VERSION 5.8 ;
BUSBITCHARS "[]" ;
DIVIDERCHAR "/" ;
UNITS
    DATABASE MICRONS 1000 ;
END UNITS

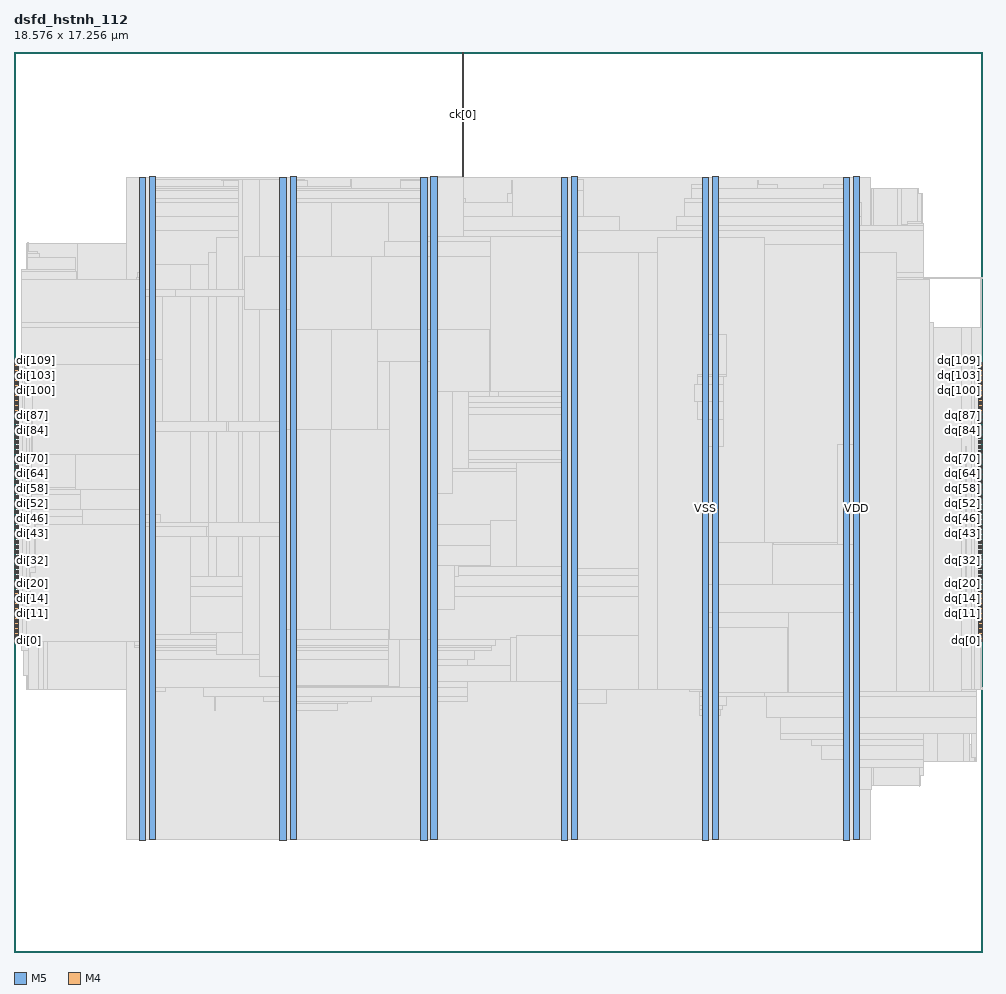
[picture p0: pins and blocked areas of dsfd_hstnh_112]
MACRO dsfd_hstnh_112
  FOREIGN dsfd_hstnh_112 0 0 ;
  CLASS BLOCK ;
  SIZE 18.576 BY 17.256 ;
  PIN ck[0]
    DIRECTION INPUT ;
    USE SIGNAL ;
    PORT
      LAYER M5 ;
        RECT  8.592 17.172 8.616 17.256 ;
    END
    PORT
      LAYER M5 ;
        RECT  8.592 14.873 8.616 17.232 ;
    END
  END ck[0]
  PIN di[0]
    DIRECTION INPUT ;
    USE SIGNAL ;
    PORT
      LAYER M4 ;
        RECT  0 5.952 0.084 5.976 ;
    END
  END di[0]
  PIN di[100]
    DIRECTION INPUT ;
    USE SIGNAL ;
    PORT
      LAYER M4 ;
        RECT  0 10.752 0.084 10.776 ;
    END
  END di[100]
  PIN di[101]
    DIRECTION INPUT ;
    USE SIGNAL ;
    PORT
      LAYER M4 ;
        RECT  0 10.8 0.084 10.824 ;
    END
  END di[101]
  PIN di[102]
    DIRECTION INPUT ;
    USE SIGNAL ;
    PORT
      LAYER M4 ;
        RECT  0 10.848 0.084 10.872 ;
    END
  END di[102]
  PIN di[103]
    DIRECTION INPUT ;
    USE SIGNAL ;
    PORT
      LAYER M4 ;
        RECT  0 10.896 0.084 10.92 ;
    END
  END di[103]
  PIN di[104]
    DIRECTION INPUT ;
    USE SIGNAL ;
    PORT
      LAYER M4 ;
        RECT  0 10.944 0.084 10.968 ;
    END
  END di[104]
  PIN di[105]
    DIRECTION INPUT ;
    USE SIGNAL ;
    PORT
      LAYER M4 ;
        RECT  0 10.992 0.084 11.016 ;
    END
  END di[105]
  PIN di[106]
    DIRECTION INPUT ;
    USE SIGNAL ;
    PORT
      LAYER M4 ;
        RECT  0 11.04 0.084 11.064 ;
    END
  END di[106]
  PIN di[107]
    DIRECTION INPUT ;
    USE SIGNAL ;
    PORT
      LAYER M4 ;
        RECT  0 11.088 0.084 11.112 ;
    END
  END di[107]
  PIN di[108]
    DIRECTION INPUT ;
    USE SIGNAL ;
    PORT
      LAYER M4 ;
        RECT  0 11.136 0.084 11.16 ;
    END
  END di[108]
  PIN di[109]
    DIRECTION INPUT ;
    USE SIGNAL ;
    PORT
      LAYER M4 ;
        RECT  0 11.184 0.084 11.208 ;
    END
  END di[109]
  PIN di[10]
    DIRECTION INPUT ;
    USE SIGNAL ;
    PORT
      LAYER M4 ;
        RECT  0 6.432 0.084 6.456 ;
    END
  END di[10]
  PIN di[110]
    DIRECTION INPUT ;
    USE SIGNAL ;
    PORT
      LAYER M4 ;
        RECT  0 11.232 0.084 11.256 ;
    END
  END di[110]
  PIN di[111]
    DIRECTION INPUT ;
    USE SIGNAL ;
    PORT
      LAYER M4 ;
        RECT  0 11.28 0.084 11.304 ;
    END
  END di[111]
  PIN di[11]
    DIRECTION INPUT ;
    USE SIGNAL ;
    PORT
      LAYER M4 ;
        RECT  0 6.48 0.084 6.504 ;
    END
  END di[11]
  PIN di[12]
    DIRECTION INPUT ;
    USE SIGNAL ;
    PORT
      LAYER M4 ;
        RECT  0 6.528 0.084 6.552 ;
    END
  END di[12]
  PIN di[13]
    DIRECTION INPUT ;
    USE SIGNAL ;
    PORT
      LAYER M4 ;
        RECT  0 6.576 0.084 6.6 ;
    END
  END di[13]
  PIN di[14]
    DIRECTION INPUT ;
    USE SIGNAL ;
    PORT
      LAYER M4 ;
        RECT  0 6.624 0.084 6.648 ;
    END
  END di[14]
  PIN di[15]
    DIRECTION INPUT ;
    USE SIGNAL ;
    PORT
      LAYER M4 ;
        RECT  0 6.672 0.084 6.696 ;
    END
  END di[15]
  PIN di[16]
    DIRECTION INPUT ;
    USE SIGNAL ;
    PORT
      LAYER M4 ;
        RECT  0 6.72 0.084 6.744 ;
    END
  END di[16]
  PIN di[17]
    DIRECTION INPUT ;
    USE SIGNAL ;
    PORT
      LAYER M4 ;
        RECT  0 6.768 0.084 6.792 ;
    END
  END di[17]
  PIN di[18]
    DIRECTION INPUT ;
    USE SIGNAL ;
    PORT
      LAYER M4 ;
        RECT  0 6.816 0.084 6.84 ;
    END
  END di[18]
  PIN di[19]
    DIRECTION INPUT ;
    USE SIGNAL ;
    PORT
      LAYER M4 ;
        RECT  0 6.864 0.084 6.888 ;
    END
  END di[19]
  PIN di[1]
    DIRECTION INPUT ;
    USE SIGNAL ;
    PORT
      LAYER M4 ;
        RECT  0 6 0.084 6.024 ;
    END
  END di[1]
  PIN di[20]
    DIRECTION INPUT ;
    USE SIGNAL ;
    PORT
      LAYER M4 ;
        RECT  0 6.912 0.084 6.936 ;
    END
  END di[20]
  PIN di[21]
    DIRECTION INPUT ;
    USE SIGNAL ;
    PORT
      LAYER M4 ;
        RECT  0 6.96 0.084 6.984 ;
    END
  END di[21]
  PIN di[22]
    DIRECTION INPUT ;
    USE SIGNAL ;
    PORT
      LAYER M4 ;
        RECT  0 7.008 0.084 7.032 ;
    END
  END di[22]
  PIN di[23]
    DIRECTION INPUT ;
    USE SIGNAL ;
    PORT
      LAYER M4 ;
        RECT  0 7.056 0.084 7.08 ;
    END
  END di[23]
  PIN di[24]
    DIRECTION INPUT ;
    USE SIGNAL ;
    PORT
      LAYER M4 ;
        RECT  0 7.104 0.084 7.128 ;
    END
  END di[24]
  PIN di[25]
    DIRECTION INPUT ;
    USE SIGNAL ;
    PORT
      LAYER M4 ;
        RECT  0 7.152 0.084 7.176 ;
    END
  END di[25]
  PIN di[26]
    DIRECTION INPUT ;
    USE SIGNAL ;
    PORT
      LAYER M4 ;
        RECT  0 7.2 0.084 7.224 ;
    END
  END di[26]
  PIN di[27]
    DIRECTION INPUT ;
    USE SIGNAL ;
    PORT
      LAYER M4 ;
        RECT  0 7.248 0.084 7.272 ;
    END
  END di[27]
  PIN di[28]
    DIRECTION INPUT ;
    USE SIGNAL ;
    PORT
      LAYER M4 ;
        RECT  0 7.296 0.084 7.32 ;
    END
  END di[28]
  PIN di[29]
    DIRECTION INPUT ;
    USE SIGNAL ;
    PORT
      LAYER M4 ;
        RECT  0 7.344 0.084 7.368 ;
    END
  END di[29]
  PIN di[2]
    DIRECTION INPUT ;
    USE SIGNAL ;
    PORT
      LAYER M4 ;
        RECT  0 6.048 0.084 6.072 ;
    END
  END di[2]
  PIN di[30]
    DIRECTION INPUT ;
    USE SIGNAL ;
    PORT
      LAYER M4 ;
        RECT  0 7.392 0.084 7.416 ;
    END
  END di[30]
  PIN di[31]
    DIRECTION INPUT ;
    USE SIGNAL ;
    PORT
      LAYER M4 ;
        RECT  0 7.44 0.084 7.464 ;
    END
  END di[31]
  PIN di[32]
    DIRECTION INPUT ;
    USE SIGNAL ;
    PORT
      LAYER M4 ;
        RECT  0 7.488 0.084 7.512 ;
    END
  END di[32]
  PIN di[33]
    DIRECTION INPUT ;
    USE SIGNAL ;
    PORT
      LAYER M4 ;
        RECT  0 7.536 0.084 7.56 ;
    END
  END di[33]
  PIN di[34]
    DIRECTION INPUT ;
    USE SIGNAL ;
    PORT
      LAYER M4 ;
        RECT  0 7.584 0.084 7.608 ;
    END
  END di[34]
  PIN di[35]
    DIRECTION INPUT ;
    USE SIGNAL ;
    PORT
      LAYER M4 ;
        RECT  0 7.632 0.084 7.656 ;
    END
  END di[35]
  PIN di[36]
    DIRECTION INPUT ;
    USE SIGNAL ;
    PORT
      LAYER M4 ;
        RECT  0 7.68 0.084 7.704 ;
    END
  END di[36]
  PIN di[37]
    DIRECTION INPUT ;
    USE SIGNAL ;
    PORT
      LAYER M4 ;
        RECT  0 7.728 0.084 7.752 ;
    END
  END di[37]
  PIN di[38]
    DIRECTION INPUT ;
    USE SIGNAL ;
    PORT
      LAYER M4 ;
        RECT  0 7.776 0.084 7.8 ;
    END
  END di[38]
  PIN di[39]
    DIRECTION INPUT ;
    USE SIGNAL ;
    PORT
      LAYER M4 ;
        RECT  0 7.824 0.084 7.848 ;
    END
  END di[39]
  PIN di[3]
    DIRECTION INPUT ;
    USE SIGNAL ;
    PORT
      LAYER M4 ;
        RECT  0 6.096 0.084 6.12 ;
    END
  END di[3]
  PIN di[40]
    DIRECTION INPUT ;
    USE SIGNAL ;
    PORT
      LAYER M4 ;
        RECT  0 7.872 0.084 7.896 ;
    END
  END di[40]
  PIN di[41]
    DIRECTION INPUT ;
    USE SIGNAL ;
    PORT
      LAYER M4 ;
        RECT  0 7.92 0.084 7.944 ;
    END
  END di[41]
  PIN di[42]
    DIRECTION INPUT ;
    USE SIGNAL ;
    PORT
      LAYER M4 ;
        RECT  0 7.968 0.084 7.992 ;
    END
  END di[42]
  PIN di[43]
    DIRECTION INPUT ;
    USE SIGNAL ;
    PORT
      LAYER M4 ;
        RECT  0 8.016 0.084 8.04 ;
    END
  END di[43]
  PIN di[44]
    DIRECTION INPUT ;
    USE SIGNAL ;
    PORT
      LAYER M4 ;
        RECT  0 8.064 0.084 8.088 ;
    END
  END di[44]
  PIN di[45]
    DIRECTION INPUT ;
    USE SIGNAL ;
    PORT
      LAYER M4 ;
        RECT  0 8.112 0.084 8.136 ;
    END
  END di[45]
  PIN di[46]
    DIRECTION INPUT ;
    USE SIGNAL ;
    PORT
      LAYER M4 ;
        RECT  0 8.16 0.084 8.184 ;
    END
  END di[46]
  PIN di[47]
    DIRECTION INPUT ;
    USE SIGNAL ;
    PORT
      LAYER M4 ;
        RECT  0 8.208 0.084 8.232 ;
    END
  END di[47]
  PIN di[48]
    DIRECTION INPUT ;
    USE SIGNAL ;
    PORT
      LAYER M4 ;
        RECT  0 8.256 0.084 8.28 ;
    END
  END di[48]
  PIN di[49]
    DIRECTION INPUT ;
    USE SIGNAL ;
    PORT
      LAYER M4 ;
        RECT  0 8.304 0.084 8.328 ;
    END
  END di[49]
  PIN di[4]
    DIRECTION INPUT ;
    USE SIGNAL ;
    PORT
      LAYER M4 ;
        RECT  0 6.144 0.084 6.168 ;
    END
  END di[4]
  PIN di[50]
    DIRECTION INPUT ;
    USE SIGNAL ;
    PORT
      LAYER M4 ;
        RECT  0 8.352 0.084 8.376 ;
    END
  END di[50]
  PIN di[51]
    DIRECTION INPUT ;
    USE SIGNAL ;
    PORT
      LAYER M4 ;
        RECT  0 8.4 0.084 8.424 ;
    END
  END di[51]
  PIN di[52]
    DIRECTION INPUT ;
    USE SIGNAL ;
    PORT
      LAYER M4 ;
        RECT  0 8.448 0.084 8.472 ;
    END
  END di[52]
  PIN di[53]
    DIRECTION INPUT ;
    USE SIGNAL ;
    PORT
      LAYER M4 ;
        RECT  0 8.496 0.084 8.52 ;
    END
  END di[53]
  PIN di[54]
    DIRECTION INPUT ;
    USE SIGNAL ;
    PORT
      LAYER M4 ;
        RECT  0 8.544 0.084 8.568 ;
    END
  END di[54]
  PIN di[55]
    DIRECTION INPUT ;
    USE SIGNAL ;
    PORT
      LAYER M4 ;
        RECT  0 8.592 0.084 8.616 ;
    END
  END di[55]
  PIN di[56]
    DIRECTION INPUT ;
    USE SIGNAL ;
    PORT
      LAYER M4 ;
        RECT  0 8.64 0.084 8.664 ;
    END
  END di[56]
  PIN di[57]
    DIRECTION INPUT ;
    USE SIGNAL ;
    PORT
      LAYER M4 ;
        RECT  0 8.688 0.084 8.712 ;
    END
  END di[57]
  PIN di[58]
    DIRECTION INPUT ;
    USE SIGNAL ;
    PORT
      LAYER M4 ;
        RECT  0 8.736 0.084 8.76 ;
    END
  END di[58]
  PIN di[59]
    DIRECTION INPUT ;
    USE SIGNAL ;
    PORT
      LAYER M4 ;
        RECT  0 8.784 0.084 8.808 ;
    END
  END di[59]
  PIN di[5]
    DIRECTION INPUT ;
    USE SIGNAL ;
    PORT
      LAYER M4 ;
        RECT  0 6.192 0.084 6.216 ;
    END
  END di[5]
  PIN di[60]
    DIRECTION INPUT ;
    USE SIGNAL ;
    PORT
      LAYER M4 ;
        RECT  0 8.832 0.084 8.856 ;
    END
  END di[60]
  PIN di[61]
    DIRECTION INPUT ;
    USE SIGNAL ;
    PORT
      LAYER M4 ;
        RECT  0 8.88 0.084 8.904 ;
    END
  END di[61]
  PIN di[62]
    DIRECTION INPUT ;
    USE SIGNAL ;
    PORT
      LAYER M4 ;
        RECT  0 8.928 0.084 8.952 ;
    END
  END di[62]
  PIN di[63]
    DIRECTION INPUT ;
    USE SIGNAL ;
    PORT
      LAYER M4 ;
        RECT  0 8.976 0.084 9 ;
    END
  END di[63]
  PIN di[64]
    DIRECTION INPUT ;
    USE SIGNAL ;
    PORT
      LAYER M4 ;
        RECT  0 9.024 0.084 9.048 ;
    END
  END di[64]
  PIN di[65]
    DIRECTION INPUT ;
    USE SIGNAL ;
    PORT
      LAYER M4 ;
        RECT  0 9.072 0.084 9.096 ;
    END
  END di[65]
  PIN di[66]
    DIRECTION INPUT ;
    USE SIGNAL ;
    PORT
      LAYER M4 ;
        RECT  0 9.12 0.084 9.144 ;
    END
  END di[66]
  PIN di[67]
    DIRECTION INPUT ;
    USE SIGNAL ;
    PORT
      LAYER M4 ;
        RECT  0 9.168 0.084 9.192 ;
    END
  END di[67]
  PIN di[68]
    DIRECTION INPUT ;
    USE SIGNAL ;
    PORT
      LAYER M4 ;
        RECT  0 9.216 0.084 9.24 ;
    END
  END di[68]
  PIN di[69]
    DIRECTION INPUT ;
    USE SIGNAL ;
    PORT
      LAYER M4 ;
        RECT  0 9.264 0.084 9.288 ;
    END
  END di[69]
  PIN di[6]
    DIRECTION INPUT ;
    USE SIGNAL ;
    PORT
      LAYER M4 ;
        RECT  0 6.24 0.084 6.264 ;
    END
  END di[6]
  PIN di[70]
    DIRECTION INPUT ;
    USE SIGNAL ;
    PORT
      LAYER M4 ;
        RECT  0 9.312 0.084 9.336 ;
    END
  END di[70]
  PIN di[71]
    DIRECTION INPUT ;
    USE SIGNAL ;
    PORT
      LAYER M4 ;
        RECT  0 9.36 0.084 9.384 ;
    END
  END di[71]
  PIN di[72]
    DIRECTION INPUT ;
    USE SIGNAL ;
    PORT
      LAYER M4 ;
        RECT  0 9.408 0.084 9.432 ;
    END
  END di[72]
  PIN di[73]
    DIRECTION INPUT ;
    USE SIGNAL ;
    PORT
      LAYER M4 ;
        RECT  0 9.456 0.084 9.48 ;
    END
  END di[73]
  PIN di[74]
    DIRECTION INPUT ;
    USE SIGNAL ;
    PORT
      LAYER M4 ;
        RECT  0 9.504 0.084 9.528 ;
    END
  END di[74]
  PIN di[75]
    DIRECTION INPUT ;
    USE SIGNAL ;
    PORT
      LAYER M4 ;
        RECT  0 9.552 0.084 9.576 ;
    END
  END di[75]
  PIN di[76]
    DIRECTION INPUT ;
    USE SIGNAL ;
    PORT
      LAYER M4 ;
        RECT  0 9.6 0.084 9.624 ;
    END
  END di[76]
  PIN di[77]
    DIRECTION INPUT ;
    USE SIGNAL ;
    PORT
      LAYER M4 ;
        RECT  0 9.648 0.084 9.672 ;
    END
  END di[77]
  PIN di[78]
    DIRECTION INPUT ;
    USE SIGNAL ;
    PORT
      LAYER M4 ;
        RECT  0 9.696 0.084 9.72 ;
    END
  END di[78]
  PIN di[79]
    DIRECTION INPUT ;
    USE SIGNAL ;
    PORT
      LAYER M4 ;
        RECT  0 9.744 0.084 9.768 ;
    END
  END di[79]
  PIN di[7]
    DIRECTION INPUT ;
    USE SIGNAL ;
    PORT
      LAYER M4 ;
        RECT  0 6.288 0.084 6.312 ;
    END
  END di[7]
  PIN di[80]
    DIRECTION INPUT ;
    USE SIGNAL ;
    PORT
      LAYER M4 ;
        RECT  0 9.792 0.084 9.816 ;
    END
  END di[80]
  PIN di[81]
    DIRECTION INPUT ;
    USE SIGNAL ;
    PORT
      LAYER M4 ;
        RECT  0 9.84 0.084 9.864 ;
    END
  END di[81]
  PIN di[82]
    DIRECTION INPUT ;
    USE SIGNAL ;
    PORT
      LAYER M4 ;
        RECT  0 9.888 0.084 9.912 ;
    END
  END di[82]
  PIN di[83]
    DIRECTION INPUT ;
    USE SIGNAL ;
    PORT
      LAYER M4 ;
        RECT  0 9.936 0.084 9.96 ;
    END
  END di[83]
  PIN di[84]
    DIRECTION INPUT ;
    USE SIGNAL ;
    PORT
      LAYER M4 ;
        RECT  0 9.984 0.084 10.008 ;
    END
  END di[84]
  PIN di[85]
    DIRECTION INPUT ;
    USE SIGNAL ;
    PORT
      LAYER M4 ;
        RECT  0 10.032 0.084 10.056 ;
    END
  END di[85]
  PIN di[86]
    DIRECTION INPUT ;
    USE SIGNAL ;
    PORT
      LAYER M4 ;
        RECT  0 10.08 0.084 10.104 ;
    END
  END di[86]
  PIN di[87]
    DIRECTION INPUT ;
    USE SIGNAL ;
    PORT
      LAYER M4 ;
        RECT  0 10.128 0.084 10.152 ;
    END
  END di[87]
  PIN di[88]
    DIRECTION INPUT ;
    USE SIGNAL ;
    PORT
      LAYER M4 ;
        RECT  0 10.176 0.084 10.2 ;
    END
  END di[88]
  PIN di[89]
    DIRECTION INPUT ;
    USE SIGNAL ;
    PORT
      LAYER M4 ;
        RECT  0 10.224 0.084 10.248 ;
    END
  END di[89]
  PIN di[8]
    DIRECTION INPUT ;
    USE SIGNAL ;
    PORT
      LAYER M4 ;
        RECT  0 6.336 0.084 6.36 ;
    END
  END di[8]
  PIN di[90]
    DIRECTION INPUT ;
    USE SIGNAL ;
    PORT
      LAYER M4 ;
        RECT  0 10.272 0.084 10.296 ;
    END
  END di[90]
  PIN di[91]
    DIRECTION INPUT ;
    USE SIGNAL ;
    PORT
      LAYER M4 ;
        RECT  0 10.32 0.084 10.344 ;
    END
  END di[91]
  PIN di[92]
    DIRECTION INPUT ;
    USE SIGNAL ;
    PORT
      LAYER M4 ;
        RECT  0 10.368 0.084 10.392 ;
    END
  END di[92]
  PIN di[93]
    DIRECTION INPUT ;
    USE SIGNAL ;
    PORT
      LAYER M4 ;
        RECT  0 10.416 0.084 10.44 ;
    END
  END di[93]
  PIN di[94]
    DIRECTION INPUT ;
    USE SIGNAL ;
    PORT
      LAYER M4 ;
        RECT  0 10.464 0.084 10.488 ;
    END
  END di[94]
  PIN di[95]
    DIRECTION INPUT ;
    USE SIGNAL ;
    PORT
      LAYER M4 ;
        RECT  0 10.512 0.084 10.536 ;
    END
  END di[95]
  PIN di[96]
    DIRECTION INPUT ;
    USE SIGNAL ;
    PORT
      LAYER M4 ;
        RECT  0 10.56 0.084 10.584 ;
    END
  END di[96]
  PIN di[97]
    DIRECTION INPUT ;
    USE SIGNAL ;
    PORT
      LAYER M4 ;
        RECT  0 10.608 0.084 10.632 ;
    END
  END di[97]
  PIN di[98]
    DIRECTION INPUT ;
    USE SIGNAL ;
    PORT
      LAYER M4 ;
        RECT  0 10.656 0.084 10.68 ;
    END
  END di[98]
  PIN di[99]
    DIRECTION INPUT ;
    USE SIGNAL ;
    PORT
      LAYER M4 ;
        RECT  0 10.704 0.084 10.728 ;
    END
  END di[99]
  PIN di[9]
    DIRECTION INPUT ;
    USE SIGNAL ;
    PORT
      LAYER M4 ;
        RECT  0 6.384 0.084 6.408 ;
    END
  END di[9]
  PIN dq[0]
    DIRECTION OUTPUT ;
    USE SIGNAL ;
    PORT
      LAYER M4 ;
        RECT  18.492 5.952 18.576 5.976 ;
    END
  END dq[0]
  PIN dq[100]
    DIRECTION OUTPUT ;
    USE SIGNAL ;
    PORT
      LAYER M4 ;
        RECT  18.492 10.752 18.576 10.776 ;
    END
  END dq[100]
  PIN dq[101]
    DIRECTION OUTPUT ;
    USE SIGNAL ;
    PORT
      LAYER M4 ;
        RECT  18.492 10.8 18.576 10.824 ;
    END
  END dq[101]
  PIN dq[102]
    DIRECTION OUTPUT ;
    USE SIGNAL ;
    PORT
      LAYER M4 ;
        RECT  18.492 10.848 18.576 10.872 ;
    END
  END dq[102]
  PIN dq[103]
    DIRECTION OUTPUT ;
    USE SIGNAL ;
    PORT
      LAYER M4 ;
        RECT  18.492 10.896 18.576 10.92 ;
    END
  END dq[103]
  PIN dq[104]
    DIRECTION OUTPUT ;
    USE SIGNAL ;
    PORT
      LAYER M4 ;
        RECT  18.492 10.944 18.576 10.968 ;
    END
  END dq[104]
  PIN dq[105]
    DIRECTION OUTPUT ;
    USE SIGNAL ;
    PORT
      LAYER M4 ;
        RECT  18.492 10.992 18.576 11.016 ;
    END
  END dq[105]
  PIN dq[106]
    DIRECTION OUTPUT ;
    USE SIGNAL ;
    PORT
      LAYER M4 ;
        RECT  18.492 11.04 18.576 11.064 ;
    END
  END dq[106]
  PIN dq[107]
    DIRECTION OUTPUT ;
    USE SIGNAL ;
    PORT
      LAYER M4 ;
        RECT  18.492 11.088 18.576 11.112 ;
    END
  END dq[107]
  PIN dq[108]
    DIRECTION OUTPUT ;
    USE SIGNAL ;
    PORT
      LAYER M4 ;
        RECT  18.492 11.136 18.576 11.16 ;
    END
  END dq[108]
  PIN dq[109]
    DIRECTION OUTPUT ;
    USE SIGNAL ;
    PORT
      LAYER M4 ;
        RECT  18.492 11.184 18.576 11.208 ;
    END
  END dq[109]
  PIN dq[10]
    DIRECTION OUTPUT ;
    USE SIGNAL ;
    PORT
      LAYER M4 ;
        RECT  18.492 6.432 18.576 6.456 ;
    END
  END dq[10]
  PIN dq[110]
    DIRECTION OUTPUT ;
    USE SIGNAL ;
    PORT
      LAYER M4 ;
        RECT  18.492 11.232 18.576 11.256 ;
    END
  END dq[110]
  PIN dq[111]
    DIRECTION OUTPUT ;
    USE SIGNAL ;
    PORT
      LAYER M4 ;
        RECT  18.492 11.28 18.576 11.304 ;
    END
  END dq[111]
  PIN dq[11]
    DIRECTION OUTPUT ;
    USE SIGNAL ;
    PORT
      LAYER M4 ;
        RECT  18.492 6.48 18.576 6.504 ;
    END
  END dq[11]
  PIN dq[12]
    DIRECTION OUTPUT ;
    USE SIGNAL ;
    PORT
      LAYER M4 ;
        RECT  18.492 6.528 18.576 6.552 ;
    END
  END dq[12]
  PIN dq[13]
    DIRECTION OUTPUT ;
    USE SIGNAL ;
    PORT
      LAYER M4 ;
        RECT  18.492 6.576 18.576 6.6 ;
    END
  END dq[13]
  PIN dq[14]
    DIRECTION OUTPUT ;
    USE SIGNAL ;
    PORT
      LAYER M4 ;
        RECT  18.492 6.624 18.576 6.648 ;
    END
  END dq[14]
  PIN dq[15]
    DIRECTION OUTPUT ;
    USE SIGNAL ;
    PORT
      LAYER M4 ;
        RECT  18.492 6.672 18.576 6.696 ;
    END
  END dq[15]
  PIN dq[16]
    DIRECTION OUTPUT ;
    USE SIGNAL ;
    PORT
      LAYER M4 ;
        RECT  18.492 6.72 18.576 6.744 ;
    END
  END dq[16]
  PIN dq[17]
    DIRECTION OUTPUT ;
    USE SIGNAL ;
    PORT
      LAYER M4 ;
        RECT  18.492 6.768 18.576 6.792 ;
    END
  END dq[17]
  PIN dq[18]
    DIRECTION OUTPUT ;
    USE SIGNAL ;
    PORT
      LAYER M4 ;
        RECT  18.492 6.816 18.576 6.84 ;
    END
  END dq[18]
  PIN dq[19]
    DIRECTION OUTPUT ;
    USE SIGNAL ;
    PORT
      LAYER M4 ;
        RECT  18.492 6.864 18.576 6.888 ;
    END
  END dq[19]
  PIN dq[1]
    DIRECTION OUTPUT ;
    USE SIGNAL ;
    PORT
      LAYER M4 ;
        RECT  18.492 6 18.576 6.024 ;
    END
  END dq[1]
  PIN dq[20]
    DIRECTION OUTPUT ;
    USE SIGNAL ;
    PORT
      LAYER M4 ;
        RECT  18.492 6.912 18.576 6.936 ;
    END
  END dq[20]
  PIN dq[21]
    DIRECTION OUTPUT ;
    USE SIGNAL ;
    PORT
      LAYER M4 ;
        RECT  18.492 6.96 18.576 6.984 ;
    END
  END dq[21]
  PIN dq[22]
    DIRECTION OUTPUT ;
    USE SIGNAL ;
    PORT
      LAYER M4 ;
        RECT  18.492 7.008 18.576 7.032 ;
    END
  END dq[22]
  PIN dq[23]
    DIRECTION OUTPUT ;
    USE SIGNAL ;
    PORT
      LAYER M4 ;
        RECT  18.492 7.056 18.576 7.08 ;
    END
  END dq[23]
  PIN dq[24]
    DIRECTION OUTPUT ;
    USE SIGNAL ;
    PORT
      LAYER M4 ;
        RECT  18.492 7.104 18.576 7.128 ;
    END
  END dq[24]
  PIN dq[25]
    DIRECTION OUTPUT ;
    USE SIGNAL ;
    PORT
      LAYER M4 ;
        RECT  18.492 7.152 18.576 7.176 ;
    END
  END dq[25]
  PIN dq[26]
    DIRECTION OUTPUT ;
    USE SIGNAL ;
    PORT
      LAYER M4 ;
        RECT  18.492 7.2 18.576 7.224 ;
    END
  END dq[26]
  PIN dq[27]
    DIRECTION OUTPUT ;
    USE SIGNAL ;
    PORT
      LAYER M4 ;
        RECT  18.492 7.248 18.576 7.272 ;
    END
  END dq[27]
  PIN dq[28]
    DIRECTION OUTPUT ;
    USE SIGNAL ;
    PORT
      LAYER M4 ;
        RECT  18.492 7.296 18.576 7.32 ;
    END
  END dq[28]
  PIN dq[29]
    DIRECTION OUTPUT ;
    USE SIGNAL ;
    PORT
      LAYER M4 ;
        RECT  18.492 7.344 18.576 7.368 ;
    END
  END dq[29]
  PIN dq[2]
    DIRECTION OUTPUT ;
    USE SIGNAL ;
    PORT
      LAYER M4 ;
        RECT  18.492 6.048 18.576 6.072 ;
    END
  END dq[2]
  PIN dq[30]
    DIRECTION OUTPUT ;
    USE SIGNAL ;
    PORT
      LAYER M4 ;
        RECT  18.492 7.392 18.576 7.416 ;
    END
  END dq[30]
  PIN dq[31]
    DIRECTION OUTPUT ;
    USE SIGNAL ;
    PORT
      LAYER M4 ;
        RECT  18.492 7.44 18.576 7.464 ;
    END
  END dq[31]
  PIN dq[32]
    DIRECTION OUTPUT ;
    USE SIGNAL ;
    PORT
      LAYER M4 ;
        RECT  18.492 7.488 18.576 7.512 ;
    END
  END dq[32]
  PIN dq[33]
    DIRECTION OUTPUT ;
    USE SIGNAL ;
    PORT
      LAYER M4 ;
        RECT  18.492 7.536 18.576 7.56 ;
    END
  END dq[33]
  PIN dq[34]
    DIRECTION OUTPUT ;
    USE SIGNAL ;
    PORT
      LAYER M4 ;
        RECT  18.492 7.584 18.576 7.608 ;
    END
  END dq[34]
  PIN dq[35]
    DIRECTION OUTPUT ;
    USE SIGNAL ;
    PORT
      LAYER M4 ;
        RECT  18.492 7.632 18.576 7.656 ;
    END
  END dq[35]
  PIN dq[36]
    DIRECTION OUTPUT ;
    USE SIGNAL ;
    PORT
      LAYER M4 ;
        RECT  18.492 7.68 18.576 7.704 ;
    END
  END dq[36]
  PIN dq[37]
    DIRECTION OUTPUT ;
    USE SIGNAL ;
    PORT
      LAYER M4 ;
        RECT  18.492 7.728 18.576 7.752 ;
    END
  END dq[37]
  PIN dq[38]
    DIRECTION OUTPUT ;
    USE SIGNAL ;
    PORT
      LAYER M4 ;
        RECT  18.492 7.776 18.576 7.8 ;
    END
  END dq[38]
  PIN dq[39]
    DIRECTION OUTPUT ;
    USE SIGNAL ;
    PORT
      LAYER M4 ;
        RECT  18.492 7.824 18.576 7.848 ;
    END
  END dq[39]
  PIN dq[3]
    DIRECTION OUTPUT ;
    USE SIGNAL ;
    PORT
      LAYER M4 ;
        RECT  18.492 6.096 18.576 6.12 ;
    END
  END dq[3]
  PIN dq[40]
    DIRECTION OUTPUT ;
    USE SIGNAL ;
    PORT
      LAYER M4 ;
        RECT  18.492 7.872 18.576 7.896 ;
    END
  END dq[40]
  PIN dq[41]
    DIRECTION OUTPUT ;
    USE SIGNAL ;
    PORT
      LAYER M4 ;
        RECT  18.492 7.92 18.576 7.944 ;
    END
  END dq[41]
  PIN dq[42]
    DIRECTION OUTPUT ;
    USE SIGNAL ;
    PORT
      LAYER M4 ;
        RECT  18.492 7.968 18.576 7.992 ;
    END
  END dq[42]
  PIN dq[43]
    DIRECTION OUTPUT ;
    USE SIGNAL ;
    PORT
      LAYER M4 ;
        RECT  18.492 8.016 18.576 8.04 ;
    END
  END dq[43]
  PIN dq[44]
    DIRECTION OUTPUT ;
    USE SIGNAL ;
    PORT
      LAYER M4 ;
        RECT  18.492 8.064 18.576 8.088 ;
    END
  END dq[44]
  PIN dq[45]
    DIRECTION OUTPUT ;
    USE SIGNAL ;
    PORT
      LAYER M4 ;
        RECT  18.492 8.112 18.576 8.136 ;
    END
  END dq[45]
  PIN dq[46]
    DIRECTION OUTPUT ;
    USE SIGNAL ;
    PORT
      LAYER M4 ;
        RECT  18.492 8.16 18.576 8.184 ;
    END
  END dq[46]
  PIN dq[47]
    DIRECTION OUTPUT ;
    USE SIGNAL ;
    PORT
      LAYER M4 ;
        RECT  18.492 8.208 18.576 8.232 ;
    END
  END dq[47]
  PIN dq[48]
    DIRECTION OUTPUT ;
    USE SIGNAL ;
    PORT
      LAYER M4 ;
        RECT  18.492 8.256 18.576 8.28 ;
    END
  END dq[48]
  PIN dq[49]
    DIRECTION OUTPUT ;
    USE SIGNAL ;
    PORT
      LAYER M4 ;
        RECT  18.492 8.304 18.576 8.328 ;
    END
  END dq[49]
  PIN dq[4]
    DIRECTION OUTPUT ;
    USE SIGNAL ;
    PORT
      LAYER M4 ;
        RECT  18.492 6.144 18.576 6.168 ;
    END
  END dq[4]
  PIN dq[50]
    DIRECTION OUTPUT ;
    USE SIGNAL ;
    PORT
      LAYER M4 ;
        RECT  18.492 8.352 18.576 8.376 ;
    END
  END dq[50]
  PIN dq[51]
    DIRECTION OUTPUT ;
    USE SIGNAL ;
    PORT
      LAYER M4 ;
        RECT  18.492 8.4 18.576 8.424 ;
    END
  END dq[51]
  PIN dq[52]
    DIRECTION OUTPUT ;
    USE SIGNAL ;
    PORT
      LAYER M4 ;
        RECT  18.492 8.448 18.576 8.472 ;
    END
  END dq[52]
  PIN dq[53]
    DIRECTION OUTPUT ;
    USE SIGNAL ;
    PORT
      LAYER M4 ;
        RECT  18.492 8.496 18.576 8.52 ;
    END
  END dq[53]
  PIN dq[54]
    DIRECTION OUTPUT ;
    USE SIGNAL ;
    PORT
      LAYER M4 ;
        RECT  18.492 8.544 18.576 8.568 ;
    END
  END dq[54]
  PIN dq[55]
    DIRECTION OUTPUT ;
    USE SIGNAL ;
    PORT
      LAYER M4 ;
        RECT  18.492 8.592 18.576 8.616 ;
    END
  END dq[55]
  PIN dq[56]
    DIRECTION OUTPUT ;
    USE SIGNAL ;
    PORT
      LAYER M4 ;
        RECT  18.492 8.64 18.576 8.664 ;
    END
  END dq[56]
  PIN dq[57]
    DIRECTION OUTPUT ;
    USE SIGNAL ;
    PORT
      LAYER M4 ;
        RECT  18.492 8.688 18.576 8.712 ;
    END
  END dq[57]
  PIN dq[58]
    DIRECTION OUTPUT ;
    USE SIGNAL ;
    PORT
      LAYER M4 ;
        RECT  18.492 8.736 18.576 8.76 ;
    END
  END dq[58]
  PIN dq[59]
    DIRECTION OUTPUT ;
    USE SIGNAL ;
    PORT
      LAYER M4 ;
        RECT  18.492 8.784 18.576 8.808 ;
    END
  END dq[59]
  PIN dq[5]
    DIRECTION OUTPUT ;
    USE SIGNAL ;
    PORT
      LAYER M4 ;
        RECT  18.492 6.192 18.576 6.216 ;
    END
  END dq[5]
  PIN dq[60]
    DIRECTION OUTPUT ;
    USE SIGNAL ;
    PORT
      LAYER M4 ;
        RECT  18.492 8.832 18.576 8.856 ;
    END
  END dq[60]
  PIN dq[61]
    DIRECTION OUTPUT ;
    USE SIGNAL ;
    PORT
      LAYER M4 ;
        RECT  18.492 8.88 18.576 8.904 ;
    END
  END dq[61]
  PIN dq[62]
    DIRECTION OUTPUT ;
    USE SIGNAL ;
    PORT
      LAYER M4 ;
        RECT  18.492 8.928 18.576 8.952 ;
    END
  END dq[62]
  PIN dq[63]
    DIRECTION OUTPUT ;
    USE SIGNAL ;
    PORT
      LAYER M4 ;
        RECT  18.492 8.976 18.576 9 ;
    END
  END dq[63]
  PIN dq[64]
    DIRECTION OUTPUT ;
    USE SIGNAL ;
    PORT
      LAYER M4 ;
        RECT  18.492 9.024 18.576 9.048 ;
    END
  END dq[64]
  PIN dq[65]
    DIRECTION OUTPUT ;
    USE SIGNAL ;
    PORT
      LAYER M4 ;
        RECT  18.492 9.072 18.576 9.096 ;
    END
  END dq[65]
  PIN dq[66]
    DIRECTION OUTPUT ;
    USE SIGNAL ;
    PORT
      LAYER M4 ;
        RECT  18.492 9.12 18.576 9.144 ;
    END
  END dq[66]
  PIN dq[67]
    DIRECTION OUTPUT ;
    USE SIGNAL ;
    PORT
      LAYER M4 ;
        RECT  18.492 9.168 18.576 9.192 ;
    END
  END dq[67]
  PIN dq[68]
    DIRECTION OUTPUT ;
    USE SIGNAL ;
    PORT
      LAYER M4 ;
        RECT  18.492 9.216 18.576 9.24 ;
    END
  END dq[68]
  PIN dq[69]
    DIRECTION OUTPUT ;
    USE SIGNAL ;
    PORT
      LAYER M4 ;
        RECT  18.492 9.264 18.576 9.288 ;
    END
  END dq[69]
  PIN dq[6]
    DIRECTION OUTPUT ;
    USE SIGNAL ;
    PORT
      LAYER M4 ;
        RECT  18.492 6.24 18.576 6.264 ;
    END
  END dq[6]
  PIN dq[70]
    DIRECTION OUTPUT ;
    USE SIGNAL ;
    PORT
      LAYER M4 ;
        RECT  18.492 9.312 18.576 9.336 ;
    END
  END dq[70]
  PIN dq[71]
    DIRECTION OUTPUT ;
    USE SIGNAL ;
    PORT
      LAYER M4 ;
        RECT  18.492 9.36 18.576 9.384 ;
    END
  END dq[71]
  PIN dq[72]
    DIRECTION OUTPUT ;
    USE SIGNAL ;
    PORT
      LAYER M4 ;
        RECT  18.492 9.408 18.576 9.432 ;
    END
  END dq[72]
  PIN dq[73]
    DIRECTION OUTPUT ;
    USE SIGNAL ;
    PORT
      LAYER M4 ;
        RECT  18.492 9.456 18.576 9.48 ;
    END
  END dq[73]
  PIN dq[74]
    DIRECTION OUTPUT ;
    USE SIGNAL ;
    PORT
      LAYER M4 ;
        RECT  18.492 9.504 18.576 9.528 ;
    END
  END dq[74]
  PIN dq[75]
    DIRECTION OUTPUT ;
    USE SIGNAL ;
    PORT
      LAYER M4 ;
        RECT  18.492 9.552 18.576 9.576 ;
    END
  END dq[75]
  PIN dq[76]
    DIRECTION OUTPUT ;
    USE SIGNAL ;
    PORT
      LAYER M4 ;
        RECT  18.492 9.6 18.576 9.624 ;
    END
  END dq[76]
  PIN dq[77]
    DIRECTION OUTPUT ;
    USE SIGNAL ;
    PORT
      LAYER M4 ;
        RECT  18.492 9.648 18.576 9.672 ;
    END
  END dq[77]
  PIN dq[78]
    DIRECTION OUTPUT ;
    USE SIGNAL ;
    PORT
      LAYER M4 ;
        RECT  18.492 9.696 18.576 9.72 ;
    END
  END dq[78]
  PIN dq[79]
    DIRECTION OUTPUT ;
    USE SIGNAL ;
    PORT
      LAYER M4 ;
        RECT  18.492 9.744 18.576 9.768 ;
    END
  END dq[79]
  PIN dq[7]
    DIRECTION OUTPUT ;
    USE SIGNAL ;
    PORT
      LAYER M4 ;
        RECT  18.492 6.288 18.576 6.312 ;
    END
  END dq[7]
  PIN dq[80]
    DIRECTION OUTPUT ;
    USE SIGNAL ;
    PORT
      LAYER M4 ;
        RECT  18.492 9.792 18.576 9.816 ;
    END
  END dq[80]
  PIN dq[81]
    DIRECTION OUTPUT ;
    USE SIGNAL ;
    PORT
      LAYER M4 ;
        RECT  18.492 9.84 18.576 9.864 ;
    END
  END dq[81]
  PIN dq[82]
    DIRECTION OUTPUT ;
    USE SIGNAL ;
    PORT
      LAYER M4 ;
        RECT  18.492 9.888 18.576 9.912 ;
    END
  END dq[82]
  PIN dq[83]
    DIRECTION OUTPUT ;
    USE SIGNAL ;
    PORT
      LAYER M4 ;
        RECT  18.492 9.936 18.576 9.96 ;
    END
  END dq[83]
  PIN dq[84]
    DIRECTION OUTPUT ;
    USE SIGNAL ;
    PORT
      LAYER M4 ;
        RECT  18.492 9.984 18.576 10.008 ;
    END
  END dq[84]
  PIN dq[85]
    DIRECTION OUTPUT ;
    USE SIGNAL ;
    PORT
      LAYER M4 ;
        RECT  18.492 10.032 18.576 10.056 ;
    END
  END dq[85]
  PIN dq[86]
    DIRECTION OUTPUT ;
    USE SIGNAL ;
    PORT
      LAYER M4 ;
        RECT  18.492 10.08 18.576 10.104 ;
    END
  END dq[86]
  PIN dq[87]
    DIRECTION OUTPUT ;
    USE SIGNAL ;
    PORT
      LAYER M4 ;
        RECT  18.492 10.128 18.576 10.152 ;
    END
  END dq[87]
  PIN dq[88]
    DIRECTION OUTPUT ;
    USE SIGNAL ;
    PORT
      LAYER M4 ;
        RECT  18.492 10.176 18.576 10.2 ;
    END
  END dq[88]
  PIN dq[89]
    DIRECTION OUTPUT ;
    USE SIGNAL ;
    PORT
      LAYER M4 ;
        RECT  18.492 10.224 18.576 10.248 ;
    END
  END dq[89]
  PIN dq[8]
    DIRECTION OUTPUT ;
    USE SIGNAL ;
    PORT
      LAYER M4 ;
        RECT  18.492 6.336 18.576 6.36 ;
    END
  END dq[8]
  PIN dq[90]
    DIRECTION OUTPUT ;
    USE SIGNAL ;
    PORT
      LAYER M4 ;
        RECT  18.492 10.272 18.576 10.296 ;
    END
  END dq[90]
  PIN dq[91]
    DIRECTION OUTPUT ;
    USE SIGNAL ;
    PORT
      LAYER M4 ;
        RECT  18.492 10.32 18.576 10.344 ;
    END
  END dq[91]
  PIN dq[92]
    DIRECTION OUTPUT ;
    USE SIGNAL ;
    PORT
      LAYER M4 ;
        RECT  18.492 10.368 18.576 10.392 ;
    END
  END dq[92]
  PIN dq[93]
    DIRECTION OUTPUT ;
    USE SIGNAL ;
    PORT
      LAYER M4 ;
        RECT  18.492 10.416 18.576 10.44 ;
    END
  END dq[93]
  PIN dq[94]
    DIRECTION OUTPUT ;
    USE SIGNAL ;
    PORT
      LAYER M4 ;
        RECT  18.492 10.464 18.576 10.488 ;
    END
  END dq[94]
  PIN dq[95]
    DIRECTION OUTPUT ;
    USE SIGNAL ;
    PORT
      LAYER M4 ;
        RECT  18.492 10.512 18.576 10.536 ;
    END
  END dq[95]
  PIN dq[96]
    DIRECTION OUTPUT ;
    USE SIGNAL ;
    PORT
      LAYER M4 ;
        RECT  18.492 10.56 18.576 10.584 ;
    END
  END dq[96]
  PIN dq[97]
    DIRECTION OUTPUT ;
    USE SIGNAL ;
    PORT
      LAYER M4 ;
        RECT  18.492 10.608 18.576 10.632 ;
    END
  END dq[97]
  PIN dq[98]
    DIRECTION OUTPUT ;
    USE SIGNAL ;
    PORT
      LAYER M4 ;
        RECT  18.492 10.656 18.576 10.68 ;
    END
  END dq[98]
  PIN dq[99]
    DIRECTION OUTPUT ;
    USE SIGNAL ;
    PORT
      LAYER M4 ;
        RECT  18.492 10.704 18.576 10.728 ;
    END
  END dq[99]
  PIN dq[9]
    DIRECTION OUTPUT ;
    USE SIGNAL ;
    PORT
      LAYER M4 ;
        RECT  18.492 6.384 18.576 6.408 ;
    END
  END dq[9]
  PIN VDD
    DIRECTION INOUT ;
    USE POWER ;
    PORT
      LAYER M5 ;
        RECT  16.092 2.151 16.212 14.873 ;
        RECT  13.392 2.151 13.512 14.873 ;
        RECT  10.692 2.151 10.812 14.873 ;
        RECT  7.992 2.151 8.112 14.873 ;
        RECT  5.292 2.151 5.412 14.873 ;
        RECT  2.592 2.151 2.712 14.873 ;
    END
  END VDD
  PIN VSS
    DIRECTION INOUT ;
    USE GROUND ;
    PORT
      LAYER M5 ;
        RECT  15.9 2.137 16.02 14.859 ;
        RECT  13.2 2.137 13.32 14.859 ;
        RECT  10.5 2.137 10.62 14.859 ;
        RECT  7.8 2.137 7.92 14.859 ;
        RECT  5.1 2.137 5.22 14.859 ;
        RECT  2.4 2.137 2.52 14.859 ;
    END
  END VSS
  # OT_OBS_CLOSED layer=M5 d_um=1.536 added=22
  OBS
    LAYER RVTN ;
     RECT  2.16 2.16 16.416 2.295 ;
     RECT  2.16 2.565 16.416 2.835 ;
     RECT  2.16 3.105 16.416 3.375 ;
     RECT  2.16 3.645 16.416 3.915 ;
     RECT  2.16 4.185 16.416 4.455 ;
     RECT  2.16 4.725 16.416 4.995 ;
     RECT  2.16 5.265 16.416 5.535 ;
     RECT  2.16 5.805 16.416 6.075 ;
     RECT  2.16 6.345 16.416 6.615 ;
     RECT  2.16 6.885 16.416 7.155 ;
     RECT  2.16 7.425 16.416 7.695 ;
     RECT  2.16 7.965 16.416 8.235 ;
     RECT  2.16 8.505 16.416 8.775 ;
     RECT  2.16 9.045 16.416 9.315 ;
     RECT  2.16 9.585 16.416 9.855 ;
     RECT  2.16 10.125 16.416 10.395 ;
     RECT  2.16 10.665 16.416 10.935 ;
     RECT  2.16 11.205 16.416 11.475 ;
     RECT  2.16 11.745 16.416 12.015 ;
     RECT  2.16 12.285 16.416 12.555 ;
     RECT  2.16 12.825 16.416 13.095 ;
     RECT  2.16 13.365 16.416 13.635 ;
     RECT  2.16 13.905 16.416 14.175 ;
     RECT  2.16 14.445 16.416 14.715 ;
    LAYER RVTP ;
     RECT  2.16 2.295 16.416 2.565 ;
     RECT  2.16 2.835 16.416 3.105 ;
     RECT  2.16 3.375 16.416 3.645 ;
     RECT  2.16 3.915 16.416 4.185 ;
     RECT  2.16 4.455 16.416 4.725 ;
     RECT  2.16 4.995 16.416 5.265 ;
     RECT  2.16 5.535 16.416 5.805 ;
     RECT  2.16 6.075 16.416 6.345 ;
     RECT  2.16 6.615 16.416 6.885 ;
     RECT  2.16 7.155 16.416 7.425 ;
     RECT  2.16 7.695 16.416 7.965 ;
     RECT  2.16 8.235 16.416 8.505 ;
     RECT  2.16 8.775 16.416 9.045 ;
     RECT  2.16 9.315 16.416 9.585 ;
     RECT  2.16 9.855 16.416 10.125 ;
     RECT  2.16 10.395 16.416 10.665 ;
     RECT  2.16 10.935 16.416 11.205 ;
     RECT  2.16 11.475 16.416 11.745 ;
     RECT  2.16 12.015 16.416 12.285 ;
     RECT  2.16 12.555 16.416 12.825 ;
     RECT  2.16 13.095 16.416 13.365 ;
     RECT  2.16 13.635 16.416 13.905 ;
     RECT  2.16 14.175 16.416 14.445 ;
     RECT  2.16 14.715 16.416 14.85 ;
    LAYER M1 ;
     RECT  2.16 2.151 16.416 14.859 ;
    LAYER M2 ;
     RECT  0.103 7.974 0.139 7.992 ;
     RECT  0.103 8.901 0.139 9.612 ;
     RECT  0.103 10.791 0.139 10.809 ;
     RECT  0.139 5.778 0.175 5.796 ;
     RECT  0.139 6.894 0.175 6.912 ;
     RECT  0.139 7.74 0.175 10.809 ;
     RECT  0.139 13.068 0.211 13.086 ;
     RECT  0.175 5.31 0.247 10.809 ;
     RECT  0.211 12.636 0.247 13.086 ;
     RECT  0.247 12.636 0.283 13.59 ;
     RECT  0.247 5.04 0.463 10.809 ;
     RECT  0.463 5.04 0.571 11.466 ;
     RECT  0.571 5.04 0.635 11.844 ;
     RECT  0.635 11.448 1.219 11.844 ;
     RECT  0.283 12.6 1.219 13.59 ;
     RECT  0.635 5.04 2.16 10.494 ;
     RECT  1.219 11.448 2.16 13.59 ;
     RECT  2.16 2.151 16.416 14.859 ;
     RECT  16.416 3.114 16.439 14.634 ;
     RECT  16.439 3.186 16.475 14.634 ;
     RECT  16.475 10.134 16.943 14.634 ;
     RECT  16.943 12.906 17.015 14.634 ;
     RECT  17.015 13.95 17.339 14.634 ;
     RECT  16.475 3.186 17.375 9.108 ;
     RECT  17.339 13.95 17.411 14.544 ;
     RECT  17.375 3.384 17.447 9.108 ;
     RECT  17.411 13.95 17.447 13.968 ;
     RECT  16.943 10.134 17.519 12.078 ;
     RECT  17.447 3.654 17.699 9.108 ;
     RECT  17.519 10.134 17.771 11.97 ;
     RECT  17.699 8.55 18.103 9.108 ;
     RECT  17.771 10.134 18.103 11.736 ;
     RECT  17.699 6.048 18.131 7.758 ;
     RECT  17.699 3.654 18.203 5.139 ;
     RECT  18.203 5.121 18.239 5.139 ;
     RECT  18.203 3.654 18.311 4.284 ;
     RECT  18.103 8.55 18.311 11.736 ;
     RECT  18.311 10.251 18.347 11.736 ;
     RECT  18.311 8.55 18.383 9.108 ;
     RECT  18.311 3.654 18.419 3.978 ;
     RECT  18.131 6.858 18.419 7.758 ;
     RECT  18.383 8.55 18.419 8.649 ;
     RECT  18.347 10.251 18.419 10.809 ;
     RECT  18.419 3.654 18.455 3.672 ;
     RECT  18.419 7.236 18.455 7.758 ;
     RECT  18.347 11.718 18.455 11.736 ;
     RECT  18.131 6.048 18.491 6.066 ;
     RECT  18.455 7.74 18.491 7.758 ;
     RECT  18.419 10.251 18.491 10.458 ;
     RECT  18.419 8.631 18.563 8.649 ;
     RECT  18.491 10.44 18.563 10.458 ;
     RECT  17.015 12.906 18.563 12.924 ;
    LAYER M3 ;
     RECT  2.415 2.143 2.505 2.413 ;
     RECT  5.115 2.143 5.205 2.413 ;
     RECT  7.815 2.143 7.905 2.413 ;
     RECT  10.515 2.143 10.605 2.413 ;
     RECT  13.215 2.143 13.305 2.413 ;
     RECT  15.915 2.143 16.005 2.413 ;
     RECT  15.915 2.413 16.197 3.109 ;
     RECT  17.352 3.181 17.37 3.379 ;
     RECT  15.915 3.109 16.434 3.541 ;
     RECT  17.352 3.379 17.442 3.541 ;
     RECT  15.915 3.541 17.442 3.685 ;
     RECT  18.432 3.649 18.45 3.721 ;
     RECT  15.48 3.685 17.442 3.955 ;
     RECT  15.3 3.955 17.442 4.081 ;
     RECT  14.688 4.081 17.442 4.189 ;
     RECT  18.36 3.721 18.45 4.189 ;
     RECT  14.688 4.189 18.45 4.495 ;
     RECT  13.215 2.413 13.497 4.531 ;
     RECT  5.115 2.413 5.397 4.621 ;
     RECT  13.14 4.531 13.554 4.657 ;
     RECT  13.14 4.657 13.59 4.729 ;
     RECT  5.115 4.621 6.21 4.765 ;
     RECT  10.515 2.413 10.797 4.765 ;
     RECT  5.115 4.765 6.39 4.801 ;
     RECT  7.815 2.413 8.097 4.801 ;
     RECT  3.852 4.621 3.87 4.891 ;
     RECT  4.788 4.801 6.858 4.891 ;
     RECT  7.815 4.801 8.694 4.891 ;
     RECT  13.14 4.729 13.662 4.891 ;
     RECT  14.436 4.495 18.45 4.891 ;
     RECT  2.415 2.413 2.697 4.999 ;
     RECT  13.14 4.891 18.45 4.999 ;
     RECT  10.515 4.765 11.358 5.035 ;
     RECT  12.96 4.999 18.45 5.035 ;
     RECT  2.415 4.999 2.898 5.071 ;
     RECT  3.636 4.891 8.694 5.071 ;
     RECT  10.515 5.035 11.718 5.269 ;
     RECT  0.252 5.035 0.27 5.305 ;
     RECT  12.96 5.035 18.558 5.341 ;
     RECT  2.415 5.071 8.694 5.611 ;
     RECT  10.515 5.269 11.754 5.611 ;
     RECT  12.528 5.341 18.558 5.611 ;
     RECT  0.18 5.305 0.27 5.773 ;
     RECT  2.415 5.611 8.838 5.773 ;
     RECT  2.415 5.773 9.162 5.845 ;
     RECT  2.304 5.845 9.162 5.881 ;
     RECT  10.515 5.611 18.558 5.971 ;
     RECT  2.304 5.881 9.234 5.995 ;
     RECT  10.26 5.971 18.558 5.995 ;
     RECT  2.304 5.995 18.558 6.817 ;
     RECT  0.144 5.773 0.27 6.889 ;
     RECT  0.144 6.889 0.342 6.917 ;
     RECT  2.268 6.817 18.558 7.003 ;
     RECT  0.18 6.917 0.342 7.051 ;
     RECT  2.232 7.003 18.558 7.223 ;
     RECT  1.188 6.961 1.206 7.429 ;
     RECT  0.18 7.051 0.414 7.699 ;
     RECT  1.152 7.429 1.206 7.699 ;
     RECT  0.18 7.699 1.206 7.723 ;
     RECT  2.304 7.223 18.558 7.799 ;
     RECT  0.144 7.723 1.206 7.819 ;
     RECT  0.144 7.819 1.386 7.867 ;
     RECT  0.108 7.867 1.386 7.997 ;
     RECT  0.144 7.997 1.386 8.059 ;
     RECT  2.415 7.799 18.558 8.189 ;
     RECT  0.144 8.059 1.422 8.237 ;
     RECT  17.352 8.189 18.558 8.654 ;
     RECT  0.144 8.237 1.386 8.765 ;
     RECT  0.144 8.765 1.314 8.875 ;
     RECT  2.415 8.189 16.47 9.211 ;
     RECT  17.352 8.654 18.486 9.211 ;
     RECT  0.108 8.875 1.314 9.389 ;
     RECT  2.415 9.211 18.486 9.451 ;
     RECT  2.304 9.451 18.486 9.625 ;
     RECT  0.108 9.389 1.242 9.629 ;
     RECT  0.144 9.629 1.242 10.315 ;
     RECT  2.268 9.625 18.486 10.315 ;
     RECT  0.144 10.315 18.486 10.435 ;
     RECT  0.144 10.435 18.558 10.543 ;
     RECT  0.108 10.543 18.558 10.832 ;
     RECT  0.144 10.832 18.558 11.981 ;
     RECT  0.144 11.981 17.622 12.077 ;
     RECT  0.144 12.077 17.55 12.893 ;
     RECT  2.34 12.893 17.442 12.929 ;
     RECT  18.54 11.981 18.558 12.929 ;
     RECT  2.376 12.929 17.442 13.019 ;
     RECT  0.144 12.893 1.206 13.055 ;
     RECT  0.144 13.055 1.17 13.091 ;
     RECT  0.252 13.091 1.17 13.325 ;
     RECT  0.252 13.325 0.486 13.397 ;
     RECT  0.252 13.397 0.45 13.433 ;
     RECT  0.252 13.433 0.27 13.595 ;
     RECT  2.415 13.019 17.442 13.829 ;
     RECT  12.708 13.829 17.442 13.937 ;
     RECT  17.136 13.937 17.442 13.973 ;
     RECT  17.136 13.973 17.406 14.009 ;
     RECT  2.415 13.829 11.61 14.099 ;
     RECT  12.708 13.937 16.254 14.099 ;
     RECT  2.415 14.099 9.558 14.369 ;
     RECT  12.852 14.099 16.254 14.369 ;
     RECT  2.415 14.369 8.658 14.441 ;
     RECT  12.852 14.369 16.197 14.441 ;
     RECT  9.468 14.369 9.558 14.549 ;
     RECT  17.316 14.009 17.406 14.549 ;
     RECT  2.415 14.441 8.514 14.597 ;
     RECT  10.515 14.099 10.926 14.597 ;
     RECT  2.607 14.597 8.514 14.639 ;
     RECT  12.996 14.441 16.197 14.639 ;
     RECT  17.316 14.549 17.334 14.639 ;
     RECT  2.607 14.639 6.462 14.675 ;
     RECT  12.996 14.639 13.497 14.711 ;
     RECT  14.256 14.639 14.634 14.711 ;
     RECT  15.516 14.639 16.197 14.711 ;
     RECT  5.04 14.675 5.634 14.783 ;
     RECT  7.416 14.639 8.226 14.783 ;
     RECT  9.54 14.549 9.558 14.783 ;
     RECT  14.256 14.711 14.274 14.783 ;
     RECT  2.607 14.675 4.014 14.819 ;
     RECT  5.04 14.783 5.562 14.819 ;
     RECT  6.444 14.675 6.462 14.819 ;
     RECT  7.416 14.783 8.097 14.819 ;
     RECT  10.707 14.597 10.926 14.819 ;
     RECT  2.607 14.819 2.697 14.867 ;
     RECT  5.307 14.819 5.397 14.867 ;
     RECT  8.007 14.819 8.097 14.867 ;
     RECT  10.707 14.819 10.797 14.867 ;
     RECT  13.407 14.711 13.497 14.867 ;
     RECT  16.107 14.711 16.197 14.867 ;
    LAYER M4 ;
     RECT  0.06 5.952 0.161 11.304 ;
     RECT  0.161 5.952 0.245 11.352 ;
     RECT  0.245 5.952 2.408 11.256 ;
     RECT  2.408 2.148 2.512 14.592 ;
     RECT  2.512 2.418 2.6 14.592 ;
     RECT  2.6 2.418 2.704 14.862 ;
     RECT  2.704 6.096 3.377 13.176 ;
     RECT  3.377 7.2 3.733 13.176 ;
     RECT  3.377 6.096 3.877 6.12 ;
     RECT  3.733 7.2 3.877 13.416 ;
     RECT  3.877 7.2 4.309 13.704 ;
     RECT  3.985 14.784 4.309 14.808 ;
     RECT  3.877 5.712 4.381 6.12 ;
     RECT  4.309 7.2 4.381 14.808 ;
     RECT  4.381 5.712 4.705 14.808 ;
     RECT  4.705 5.28 5.108 14.808 ;
     RECT  5.108 2.148 5.212 14.808 ;
     RECT  5.212 2.418 5.3 14.808 ;
     RECT  5.3 2.418 5.404 14.862 ;
     RECT  5.404 6.192 6.083 14.376 ;
     RECT  5.404 5.088 7.189 5.112 ;
     RECT  6.083 6.24 7.189 14.376 ;
     RECT  7.189 5.088 7.808 14.376 ;
     RECT  7.808 2.148 7.912 14.592 ;
     RECT  7.912 2.418 8 14.592 ;
     RECT  8 2.418 8.104 14.862 ;
     RECT  8.104 8.736 8.129 13.656 ;
     RECT  8.129 8.784 8.417 13.656 ;
     RECT  8.104 6.576 8.453 7.416 ;
     RECT  8.453 7.2 8.525 7.416 ;
     RECT  8.417 9.264 8.705 13.656 ;
     RECT  8.705 10.656 9.109 13.656 ;
     RECT  8.525 7.392 9.133 7.416 ;
     RECT  9.109 10.656 9.281 13.704 ;
     RECT  8.104 5.184 9.529 5.496 ;
     RECT  9.529 5.184 9.637 6.024 ;
     RECT  9.133 7.392 9.637 8.28 ;
     RECT  8.705 9.264 9.637 9.384 ;
     RECT  9.637 5.184 10.508 6.072 ;
     RECT  9.637 7.392 10.508 9.384 ;
     RECT  9.281 10.656 10.508 13.416 ;
     RECT  10.508 2.148 10.612 14.592 ;
     RECT  10.612 2.418 10.7 14.592 ;
     RECT  10.7 2.418 10.804 14.862 ;
     RECT  10.804 5.04 11.977 6.072 ;
     RECT  10.804 7.344 11.977 13.416 ;
     RECT  11.977 5.04 12.337 13.416 ;
     RECT  12.337 5.04 13.208 13.704 ;
     RECT  13.208 2.148 13.312 14.592 ;
     RECT  13.312 2.418 13.4 14.592 ;
     RECT  13.4 2.418 13.504 14.862 ;
     RECT  13.504 4.896 14.393 13.704 ;
     RECT  14.393 4.896 15.908 13.56 ;
     RECT  15.908 2.148 16.012 14.592 ;
     RECT  16.012 2.418 16.1 14.592 ;
     RECT  16.1 2.418 16.204 14.862 ;
     RECT  16.204 4.992 16.913 13.416 ;
     RECT  16.913 4.992 17.561 12.888 ;
     RECT  17.561 4.992 17.633 12.072 ;
     RECT  17.633 4.992 18.173 11.976 ;
     RECT  18.173 5.04 18.353 11.976 ;
     RECT  18.353 5.04 18.419 11.352 ;
     RECT  18.419 5.04 18.54 11.304 ;
     RECT  18.54 5.04 18.569 5.064 ;
    LAYER M5 ;
     RECT  2.4 2.137 2.52 2.151 ;
     RECT  5.1 2.137 5.22 2.151 ;
     RECT  7.8 2.137 7.92 2.151 ;
     RECT  10.5 2.137 10.62 2.151 ;
     RECT  13.2 2.137 13.32 2.151 ;
     RECT  15.9 2.137 16.02 2.151 ;
     RECT  7.8 2.151 8.112 5.077 ;
     RECT  7.392 5.077 8.112 5.989 ;
     RECT  5.1 2.151 5.412 6.181 ;
     RECT  13.2 2.151 13.512 6.229 ;
     RECT  14.832 4.981 14.856 6.229 ;
     RECT  13.2 6.229 14.856 6.517 ;
     RECT  15.9 2.151 16.212 6.517 ;
     RECT  13.2 6.517 16.212 7.043 ;
     RECT  0.288 6.757 0.312 7.285 ;
     RECT  0.288 7.285 0.408 7.379 ;
     RECT  14.544 7.043 16.212 7.811 ;
     RECT  14.544 7.811 14.568 7.859 ;
     RECT  18.24 6.613 18.264 8.003 ;
     RECT  2.4 2.151 2.712 8.149 ;
     RECT  3.696 7.957 3.72 8.149 ;
     RECT  0.384 7.379 0.408 8.197 ;
     RECT  2.4 8.149 3.72 8.243 ;
     RECT  0.384 8.197 1.32 8.341 ;
     RECT  2.4 8.243 2.808 8.387 ;
     RECT  0.336 8.341 1.32 8.483 ;
     RECT  0.336 8.483 1.272 8.773 ;
     RECT  0.288 8.773 1.272 8.867 ;
     RECT  0.288 8.867 1.176 8.915 ;
     RECT  0.336 8.915 1.176 9.539 ;
     RECT  18.24 9.205 18.264 9.683 ;
     RECT  13.2 7.043 13.512 9.685 ;
     RECT  15.792 7.811 16.212 9.731 ;
     RECT  5.1 6.181 6.072 10.019 ;
     RECT  4.08 9.973 4.104 10.163 ;
     RECT  0.336 9.539 0.36 10.213 ;
     RECT  13.2 9.685 13.608 10.213 ;
     RECT  13.104 10.213 13.608 10.549 ;
     RECT  0.192 10.213 0.36 10.787 ;
     RECT  13.056 10.549 13.608 10.883 ;
     RECT  13.104 10.883 13.608 11.029 ;
     RECT  13.104 11.029 13.656 11.075 ;
     RECT  7.2 5.989 8.112 11.317 ;
     RECT  0.192 10.787 0.216 11.363 ;
     RECT  18.384 11.173 18.408 11.363 ;
     RECT  2.4 8.387 2.712 11.365 ;
     RECT  13.2 11.075 13.656 11.843 ;
     RECT  6.96 11.317 8.112 11.941 ;
     RECT  9.12 10.741 9.144 11.941 ;
     RECT  5.1 10.019 5.412 12.325 ;
     RECT  2.4 11.365 2.856 12.565 ;
     RECT  2.4 12.565 3.096 12.707 ;
     RECT  4.416 12.325 5.412 13.331 ;
     RECT  6.864 11.941 9.144 13.331 ;
     RECT  7.104 13.331 9.144 13.619 ;
     RECT  7.8 13.619 9.144 13.715 ;
     RECT  2.4 12.707 2.712 14.859 ;
     RECT  5.1 13.331 5.412 14.859 ;
     RECT  7.8 13.715 8.616 14.859 ;
     RECT  10.5 2.151 10.812 14.859 ;
     RECT  13.2 11.843 13.512 14.859 ;
     RECT  15.9 9.731 16.212 14.859 ;
     RECT  2.592 14.859 2.712 14.873 ;
     RECT  5.292 14.859 5.412 14.873 ;
     RECT  7.992 14.859 8.616 14.873 ;
     RECT  10.692 14.859 10.812 14.873 ;
     RECT  13.392 14.859 13.512 14.873 ;
     RECT  16.092 14.859 16.212 14.873 ;
     RECT  13.512 4.981 14.832 6.229 ;
     RECT  14.856 4.981 15.9 6.517 ;
     RECT  6.072 6.181 7.2 10.019 ;
     RECT  13.512 7.043 14.544 7.859 ;
     RECT  0.288 7.379 0.384 8.341 ;
     RECT  14.568 7.811 15.792 7.859 ;
     RECT  2.712 7.957 3.696 8.149 ;
     RECT  3.72 7.957 5.1 8.243 ;
     RECT  18.24 8.003 18.264 9.205 ;
     RECT  1.32 8.197 2.4 8.483 ;
     RECT  0.288 8.341 0.336 8.773 ;
     RECT  1.272 8.483 2.4 8.867 ;
     RECT  1.176 8.867 2.4 9.539 ;
     RECT  0.288 8.915 0.336 10.213 ;
     RECT  2.712 9.973 4.08 10.163 ;
     RECT  4.104 9.973 5.1 10.163 ;
     RECT  6.96 10.019 7.2 11.317 ;
     RECT  2.712 10.163 2.856 11.365 ;
     RECT  8.112 10.741 9.12 11.941 ;
     RECT  9.144 10.741 10.5 13.715 ;
     RECT  5.412 11.941 6.864 13.331 ;
     RECT  3.096 12.565 4.416 12.707 ;
  END
END dsfd_hstnh_112
END LIBRARY
